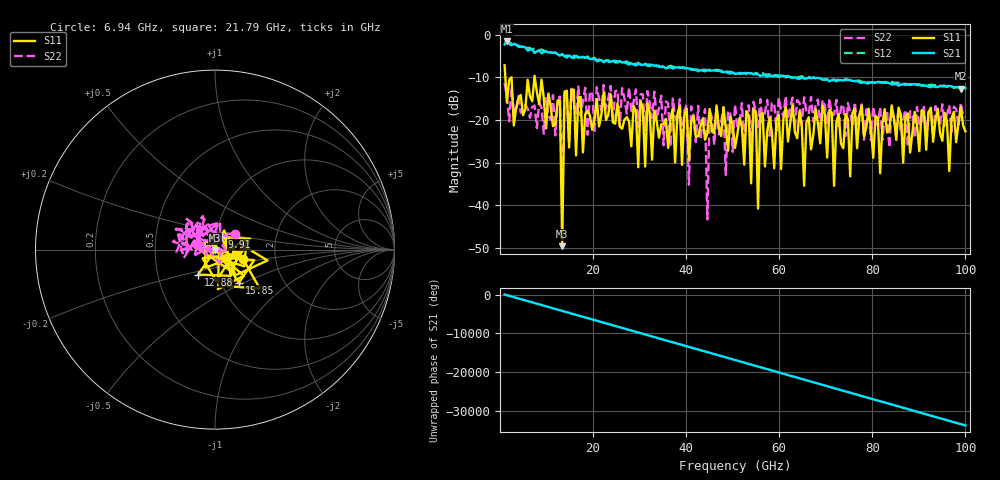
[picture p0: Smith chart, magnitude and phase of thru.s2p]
!Created with skrf (http://scikit-rf.org).
# GHz S RI R 50.0
!freq ReS11 ImS11 ReS21 ImS21 ReS12 ImS12 ReS22 ImS22
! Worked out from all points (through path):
!   201 points, 1 GHz to 100 GHz, reference 50 ohm
!   highest |S21| = -1.51 dB at 1.495 GHz (marker M1); lowest = -12.7 dB at 99.01 GHz (marker M2)
!   lowest |S11| = -49.5 dB at 13.38 GHz (marker M3), VSWR 1.01, Z = 50.1 - j0.322 ohm
!   |S11| at or under -10 dB: 1.163 GHz to 2.442 GHz (1.28 GHz wide, 71 % of centre); 2.487 GHz to 7.402 GHz (4.915 GHz wide, 99.4 % of centre); 7.487 GHz to end of sweep
!   |S22| runs from -43.3 to -11.3 dB; largest |S21 - S12| = 0.11
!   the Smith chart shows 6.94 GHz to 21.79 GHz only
!   S11 on the Smith chart (normalised r, x): 6.94 GHz: 1.36, -0.15; 9.91 GHz: 1.07, +0.15; 12.88 GHz: 0.80, -0.23; 15.85 GHz: 1.21, -0.47; 21.79 GHz: 1.25, -0.06
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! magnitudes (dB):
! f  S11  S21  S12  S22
! 1 GHz  -7.1  -2.2  -1.3  -11.3
! 1.495 GHz  -15.8  -1.5  -1.5  -14.6
! 6.94 GHz  -15.6  -3.4  -3.4  -16.9
! 9.91 GHz  -21.9  -3.8  -3.9  -14.8
! 12.88 GHz  -15.5  -4.9  -4.6  -13.9
! 13.38 GHz  -49.5  -4.6  -4.5  -38.5
! 13.87 GHz  -13.3  -5.0  -5.1  -14.0
! 15.85 GHz  -12.9  -5.5  -4.9  -15.9
! 17.83 GHz  -27.6  -5.2  -5.3  -15.5
! 21.79 GHz  -18.8  -5.9  -5.8  -17.7
! 34.16 GHz  -24.1  -7.5  -7.2  -17.2
! 40.1 GHz  -17.3  -7.8  -8.0  -16.4
! 40.6 GHz  -29.3  -7.9  -7.9  -35.2
! 44.06 GHz  -24.6  -8.6  -8.2  -17.4
! 44.56 GHz  -23.0  -8.3  -8.3  -43.3
! 45.05 GHz  -17.4  -8.4  -8.2  -17.6
! 48.52 GHz  -21.7  -8.7  -8.6  -32.8
! 50.5 GHz  -26.5  -9.2  -8.9  -16.4
! 67.33 GHz  -23.4  -10.1  -10.0  -20.3
! 83.67 GHz  -22.3  -11.3  -11.1  -26.5
! 99.01 GHz  -16.9  -12.7  -12.5  -15.9
! 100 GHz  -22.6  -12.5  -12.4  -19.3
